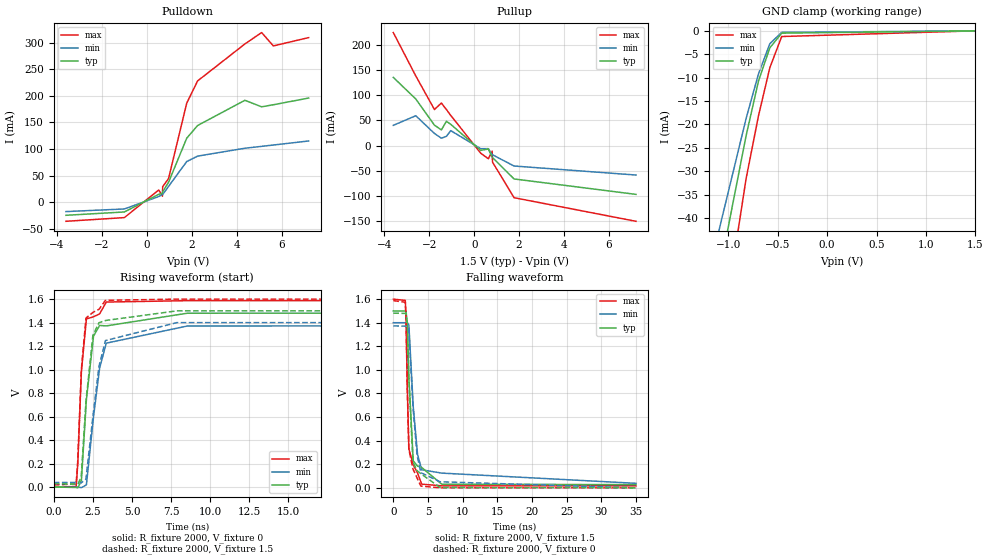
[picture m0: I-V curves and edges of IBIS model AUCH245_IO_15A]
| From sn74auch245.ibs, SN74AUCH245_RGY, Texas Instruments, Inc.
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[Model]   AUCH245_IO_15A
Model_type  3-state
Enable   Active-Low
Vref =   0
Rref =   2000
Cref =   15p
Vmeas =   0.75
| variable   typ   min   max
C_comp   7.04pF   6.32pF   7.63pF
| C_pullup   6.12pF   0.52pF   11.37pF
| C_pulldown   7.96pF   7.02pF   12.32pF
| C_tri-state   7.04pF   6.32pF   7.63pF
[Temperature Range]   40   100   -40
| Ambient temperature   25   85   -40
[Voltage range]   1.5   1.4   1.6
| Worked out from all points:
|   slope of the pulldown table from 0 to 0.225 V, typ, clamps not added: 37.5 ohm
|   slope of the pullup table from 0 to 0.225 V, typ, clamps not added: 29.9 ohm
|   GND clamp passes 1 mA (typ) near -0.50 V on its own axis
|   rising waveform, R_fixture 2000, V_fixture 0: 20-80 % time 506ps typ, 730ps min, 328ps max; typ from 0 V to 1.48 V
|   falling waveform, R_fixture 2000, V_fixture 1.5: 20-80 % time 582ps typ, 905ps min, 360ps max; typ from 1.5 V to 0.027 V
|   rising waveform, R_fixture 2000, V_fixture 1.5: 20-80 % time 501ps typ, 726ps min, 324ps max; typ from 0.027 V to 1.5 V
|   falling waveform, R_fixture 2000, V_fixture 0: 20-80 % time 583ps typ, 908ps min, 359ps max; typ from 1.48 V to 0 V
[GND Clamp]
| AUCH245_IO_15A
|   Voltage   I(typ)   I(min)   I(max)
-3.6V     -348.4mA   -291.7mA   -422.1mA
-1.41V    -88.34mA   -72.2mA    -113.8mA
-1.36V    -82.53mA   -67.43mA   -106.7mA
-1.27V    -72.14mA   -58.93mA   -93.93mA
-1.225V   -66.97mA   -54.72mA   -87.55mA
-1.115V   -54.46mA   -44.56mA   -72.01mA
-1.08V    -50.52mA   -41.37mA   -67.08mA
-820mV    -22.42mA   -18.74mA   -31.59mA
-695mV    -10.75mA   -9.22mA    -18.2mA
-580mV    -3.637mA   -2.754mA   -7.888mA
-460mV    -498.7uA   -331.2uA   -1.219mA
1.5V      904.5pA    545.7nA    20.6pA
[Pulldown]
| AUCH245_IO_15A
|   Voltage   I(typ)   I(min)   I(max)
-3.6V     -24.49mA   -17.53mA   -35.78mA
-1V       -18.24mA   -12.59mA   -28.84mA
530mV     14.93mA    10.83mA    23.06mA
695mV     16.87mA    14.39mA    11.34mA
705mV     19.65mA    14.68mA    29.43mA
965mV     37.43mA    29.69mA    44.37mA
1.775V    120.4mA    76.56mA    186.3mA
2.26V     144.3mA    86.75mA    228.1mA
4.365V    191.7mA    101.6mA    297.6mA
5.11V     179.4mA    105.1mA    319mA
5.63V     183.3mA    107.6mA    293.9mA
7.2V      195.9mA    115.2mA    309.5mA
[Pullup]
| AUCH245_IO_15A
|   Voltage   I(typ)   I(min)   I(max)
-3.6V     135.5mA    40.29mA    224.6mA
-2.6V     92.66mA    59.33mA    138.4mA
-1.77V    40.63mA    24.16mA    71.7mA
-1.46V    31.15mA    14.74mA    84.63mA
-1.235V   48.3mA     18.48mA    71.55mA
-1.045V   42.35mA    29.79mA    60.05mA
290mV     -9.433mA   -6.112mA   -15.03mA
630mV     -6.806mA   -6.067mA   -26.14mA
800mV     -23.19mA   -17.72mA   -11.18mA
815mV     -23.73mA   -18.24mA   -32.73mA
1.775V    -66.25mA   -40.56mA   -103.5mA
7.2V      -96.9mA    -58.48mA   -150.4mA
[Ramp]
| AUCH245_IO_15A
| variable   typ   min   max
dV/dt_r   0.89/5.12E-10   0.83/7.32E-10   0.96/3.34E-10
dV/dt_f   0.88/5.85E-10   0.82/9.06E-10   0.95/3.62E-10
R_load = 2000
[Rising Waveform]
| AUCH245_IO_15A
R_fixture =   2000
C_fixture =   0
L_fixture =   0
V_fixture =   0
V_fixture_min = 0
V_fixture_max = 0
|   Time   V(typ)   V(min)   V(max)
0s        11.12nV    44.9nV     761.8pV
1.43ns    -3.973mV   76.14uV    4.037mV
1.535ns   -7.306mV   -1.152mV   201.5mV
1.765ns   54.68mV    -5.732mV   985.5mV
2.085ns   745.1mV    18.57mV    1.431V
2.54ns    1.285V     598.7mV    1.45V
2.93ns    1.376V     1.012V     1.474V
3.355ns   1.372V     1.225V     1.575V
8.54ns    1.48V      1.371V     1.587V
34.99ns   1.481V     1.373V     1.587V
[Falling Waveform]
| AUCH245_IO_15A
R_fixture =   2000
C_fixture =   0
L_fixture =   0
V_fixture =   1.5
V_fixture_min = 1.4
V_fixture_max = 1.6
|   Time   V(typ)   V(min)   V(max)
0s        1.5V       1.4V       1.6V
1.725ns   1.5V       1.4V       1.589V
1.83ns    1.498V     1.401V     1.461V
2.015ns   1.402V     1.402V     851.4mV
2.245ns   934.7mV    1.38V      331.8mV
2.875ns   228.5mV    686.8mV    194.1mV
3.495ns   184.4mV    283.4mV    126.5mV
4.09ns    173mV      153.2mV    31.56mV
6.99ns    30.84mV    125mV      17.14mV
34.99ns   27.37mV    38.43mV    16.77mV
[Rising Waveform]
| AUCH245_IO_15A
R_fixture =   2000
C_fixture =   0
L_fixture =   0
V_fixture =   1.5
V_fixture_min = 1.4
V_fixture_max = 1.6
|   Time   V(typ)   V(min)   V(max)
0s        27.32mV    38.39mV    16.75mV
1.43ns    24.39mV    38.6mV     26.06mV
1.535ns   22.34mV    37.7mV     232.2mV
1.755ns   86.93mV    35.37mV    990.2mV
2.055ns   726.4mV    66.17mV    1.438V
2.5ns     1.292V     598.6mV    1.487V
2.89ns    1.399V     1.029V     1.513V
3.305ns   1.418V     1.247V     1.59V
7.87ns    1.5V       1.4V       1.6V
34.99ns   1.5V       1.4V       1.6V
[Falling Waveform]
| AUCH245_IO_15A
R_fixture =   2000
C_fixture =   0
L_fixture =   0
V_fixture =   0
V_fixture_min = 0
V_fixture_max = 0
|   Time   V(typ)   V(min)   V(max)
0s        1.481V     1.373V     1.587V
1.725ns   1.479V     1.371V     1.574V
1.83ns    1.476V     1.371V     1.447V
2.01ns    1.379V     1.371V     853.7mV
2.235ns   933.4mV    1.346V     328.5mV
2.835ns   219.9mV    687.6mV    160.1mV
3.43ns    145.1mV    274.2mV    83.57mV
3.98ns    119.6mV    128.5mV    14.56mV
6.75ns    2.99mV     51.58mV    407.2uV
34.99ns   49.25uV    36.46uV    19.8uV
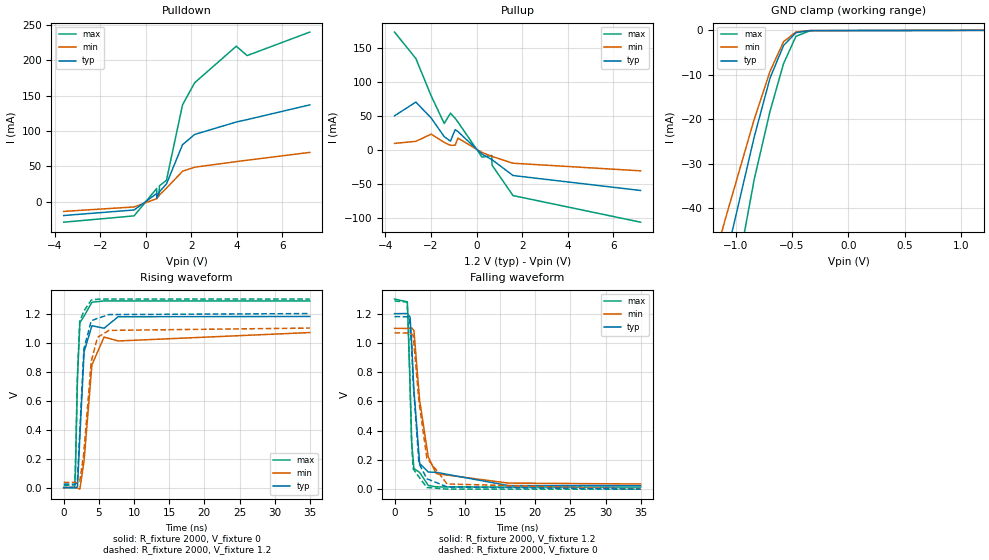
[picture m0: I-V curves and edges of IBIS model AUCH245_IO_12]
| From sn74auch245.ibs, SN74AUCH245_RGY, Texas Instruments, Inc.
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[Model]   AUCH245_IO_12
Model_type  3-state
Enable   Active-Low
Vref =   0
Rref =   2000
Cref =   15p
Vmeas =   0.6
| variable   typ   min   max
C_comp   7.13pF   6.44pF   7.70pF
| C_pullup   6.10pF   0.47pF   9.81pF
| C_pulldown   7.79pF   7.02pF   8.67pF
| C_tri-state   7.13pF   6.44pF   7.70pF
[Temperature Range]   40   100   -40
| Ambient temperature   25   85   -40
[Voltage range]   1.2   1.1   1.3
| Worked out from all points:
|   slope of the pulldown table from 0 to 0.18 V, typ, clamps not added: 42.4 ohm
|   slope of the pullup table from 0 to 0.18 V, typ, clamps not added: 39.1 ohm
|   GND clamp passes 1 mA (typ) near -0.50 V on its own axis
|   rising waveform, R_fixture 2000, V_fixture 0: 20-80 % time 703ps typ, 1.1ns min, 420ps max; typ from 0 V to 1.18 V
|   falling waveform, R_fixture 2000, V_fixture 1.2: 20-80 % time 887ps typ, 1.51ns min, 464ps max; typ from 1.2 V to 0.024 V
|   rising waveform, R_fixture 2000, V_fixture 1.2: 20-80 % time 691ps typ, 1.09ns min, 414ps max; typ from 0.024 V to 1.2 V
|   falling waveform, R_fixture 2000, V_fixture 0: 20-80 % time 880ps typ, 1.48ns min, 460ps max; typ from 1.18 V to 0 V
[GND Clamp]
| AUCH245_IO_12
|   Voltage   I(typ)   I(min)   I(max)
-3.6V     -348.4mA   -291.7mA   -422.1mA
-1.395V   -86.59mA   -70.76mA   -111.6mA
-1.345V   -80.79mA   -66.01mA   -104.5mA
-1.255V   -70.41mA   -57.52mA   -91.78mA
-1.21V    -65.25mA   -53.32mA   -85.41mA
-1.09V    -51.64mA   -42.28mA   -68.47mA
-835mV    -23.94mA   -19.97mA   -33.46mA
-695mV    -10.73mA   -9.215mA   -18.19mA
-575mV    -3.409mA   -2.552mA   -7.477mA
-465mV    -538.4uA   -354.6uA   -1.338mA
-340mV    -56.85uA   -46.84uA   -97.22uA
1.2V      742pA      544.5nA    -10.19pA
[Pulldown]
| AUCH245_IO_12
|   Voltage   I(typ)   I(min)   I(max)
-3.6V     -19.68mA   -13.85mA   -29.13mA
-510mV    -11.83mA   -7.547mA   -20.17mA
480mV     11.48mA    4.194mA    18.61mA
485mV     5.028mA    4.242mA    6.734mA
590mV     13.72mA    9.189mA    8.369mA
600mV     13.91mA    9.311mA    22.36mA
910mV     25.04mA    19.15mA    30.29mA
1.615V    80.69mA    43.04mA    137.1mA
2.15V     95.19mA    48.79mA    168.5mA
3.975V    112.8mA    56.68mA    220.2mA
4.45V     116.2mA    58.66mA    206.9mA
7.2V      137.1mA    69.78mA    240.2mA
[Pullup]
| AUCH245_IO_12
|   Voltage   I(typ)   I(min)   I(max)
-3.6V     50.58mA    10.01mA    173.6mA
-2.665V   70.72mA    13.03mA    134.8mA
-1.99V    47.23mA    23.6mA     79.7mA
-1.42V    19.97mA    11.47mA    39.36mA
-1.145V   13.31mA    7.138mA    54.39mA
-940mV    30.29mA    7.312mA    46.87mA
-815mV    27.3mA     17.76mA    41.21mA
240mV     -5.822mA   -3.33mA    -10.26mA
665mV     -13.73mA   -9.09mA    -7.68mA
680mV     -13.93mA   -9.242mA   -22.01mA
1.6V      -37.2mA    -19.13mA   -66.69mA
7.2V      -59.19mA   -30.31mA   -105.8mA
[Ramp]
| AUCH245_IO_12
| variable   typ   min   max
dV/dt_r   0.71/7.07E-10   0.65/1.11E-09   0.78/4.22E-10
dV/dt_f   0.71/8.91E-10   0.64/1.51E-09   0.77/4.65E-10
R_load = 2000
[Rising Waveform]
| AUCH245_IO_12
R_fixture =   2000
C_fixture =   0
L_fixture =   0
V_fixture =   0
V_fixture_min = 0
V_fixture_max = 0
|   Time   V(typ)   V(min)   V(max)
0s        10.41nV    46.55nV    639.7pV
1.55ns    -1.906mV   937.6uV    3.31mV
1.665ns   -3.894mV   230.5uV    107.7mV
1.965ns   7.148mV    -3.201mV   766.6mV
2.3ns     354.8mV    -10.78mV   1.136V
2.9ns     936.7mV    188.5mV    1.183V
4.01ns    1.116V     846.5mV    1.278V
5.74ns    1.099V     1.038V     1.287V
7.74ns    1.178V     1.011V     1.287V
34.99ns   1.18V      1.069V     1.287V
[Falling Waveform]
| AUCH245_IO_12
R_fixture =   2000
C_fixture =   0
L_fixture =   0
V_fixture =   1.2
V_fixture_min = 1.1
V_fixture_max = 1.3
|   Time   V(typ)   V(min)   V(max)
0s        1.2V       1.1V       1.3V
1.82ns    1.201V     1.099V     1.281V
2.21ns    1.176V     1.101V     716.1mV
2.445ns   986.6mV    1.102V     312.7mV
2.755ns   675.7mV    1.085V     140.8mV
3.57ns    175.9mV    607.6mV    114.7mV
4.79ns    117.2mV    221.8mV    25.98mV
5.925ns   115.3mV    106.2mV    15.71mV
16.2ns    24.28mV    41.45mV    14.4mV
34.99ns   24.14mV    35.41mV    14.35mV
[Rising Waveform]
| AUCH245_IO_12
R_fixture =   2000
C_fixture =   0
L_fixture =   0
V_fixture =   1.2
V_fixture_min = 1.1
V_fixture_max = 1.3
|   Time   V(typ)   V(min)   V(max)
0s        24.08mV    35.36mV    14.32mV
1.54ns    22.94mV    36.16mV    19.5mV
1.66ns    21.99mV    35.64mV    127.4mV
1.94ns    40.88mV    34.47mV    750.3mV
2.275ns   373.2mV    40.96mV    1.146V
2.865ns   955.8mV    241.4mV    1.217V
3.915ns   1.15V      870.7mV    1.293V
4.805ns   1.167V     1.036V     1.299V
6.44ns    1.193V     1.084V     1.3V
34.99ns   1.2V       1.1V       1.3V
[Falling Waveform]
| AUCH245_IO_12
R_fixture =   2000
C_fixture =   0
L_fixture =   0
V_fixture =   0
V_fixture_min = 0
V_fixture_max = 0
|   Time   V(typ)   V(min)   V(max)
0s        1.18V      1.069V     1.287V
1.765ns   1.179V     1.068V     1.28V
1.92ns    1.179V     1.068V     1.186V
2.155ns   1.162V     1.067V     802.7mV
2.415ns   985.1mV    1.063V     328.7mV
2.65ns    730.8mV    1.052V     138.9mV
3.475ns   175.8mV    598.1mV    82.99mV
4.595ns   71.52mV    213.2mV    11.62mV
7.485ns   15.13mV    35.58mV    342.9uV
34.99ns   52.7uV     35.22uV    29.29uV
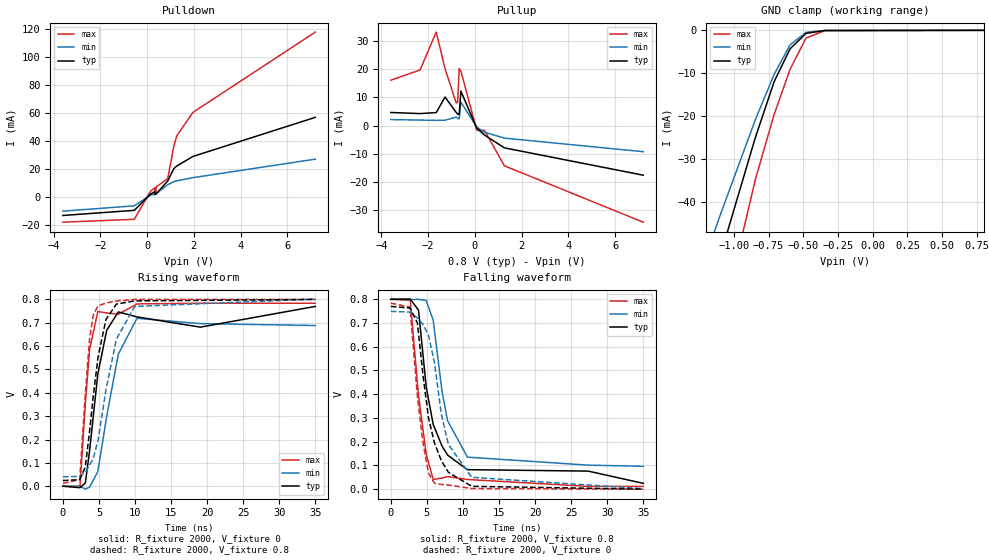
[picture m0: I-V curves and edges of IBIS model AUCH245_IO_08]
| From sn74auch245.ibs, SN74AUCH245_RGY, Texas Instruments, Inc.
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[Model]   AUCH245_IO_08
Model_type  3-state
Enable   Active-Low
Vref =   0
Rref =   2000
Cref =   15p
Vmeas =   0.4
| variable   typ   min   max
C_comp   7.24pF   6.69pF   7.71pF
| C_pullup   7.24pF   2.74pF   10.10pF
| C_pulldown   7.90pF   6.92pF   8.33pF
| C_tri-state   7.24pF   6.69pF   7.71pF
[Temperature Range]   40   100   -40
| Ambient temperature   25   85   -40
[Voltage range]   0.8   0.8   0.8
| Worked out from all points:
|   slope of the pulldown table from 0 to 0.12 V, typ, clamps not added: 71.3 ohm
|   slope of the pullup table from 0 to 0.12 V, typ, clamps not added: 92.5 ohm
|   GND clamp passes 1 mA (typ) near -0.50 V on its own axis
|   rising waveform, R_fixture 2000, V_fixture 0: 20-80 % time 1.9ns typ, 2.28ns min, 1.12ns max; typ from 0 V to 0.77 V
|   falling waveform, R_fixture 2000, V_fixture 0.8: 20-80 % time 2.9ns typ, 2.24ns min, 1.68ns max; typ from 0.8 V to 0.025 V
|   rising waveform, R_fixture 2000, V_fixture 0.8: 20-80 % time 1.87ns typ, 2.75ns min, 1.07ns max; typ from 0.024 V to 0.8 V
|   falling waveform, R_fixture 2000, V_fixture 0: 20-80 % time 2.45ns typ, 2.76ns min, 1.58ns max; typ from 0.77 V to 0 V
[GND Clamp]
| AUCH245_IO_08
|   Voltage   I(typ)   I(min)   I(max)
-3.6V     -348.4mA   -291.7mA   -422mA
-1.435V   -91.23mA   -74.58mA   -117.3mA
-1.385V   -85.42mA   -69.81mA   -110.2mA
-1.285V   -73.85mA   -60.34mA   -96.01mA
-1.24V    -68.68mA   -56.12mA   -89.63mA
-1.105V   -53.32mA   -43.64mA   -70.54mA
-845mV    -24.95mA   -20.79mA   -34.7mA
-710mV    -11.96mA   -10.26mA   -19.61mA
-595mV    -4.291mA   -3.37mA    -9.051mA
-480mV    -710.9uA   -464.9uA   -1.793mA
-345mV    -43.84uA   -41.21uA   -69.34uA
800mV     553.1pA    2.078nA    70.04pA
[Pulldown]
| AUCH245_IO_08
|   Voltage   I(typ)   I(min)   I(max)
-3.6V     -13.19mA   -10.12mA   -17.98mA
-545mV    -9.542mA   -6.309mA   -15.92mA
150mV     2.015mA    1.387mA    4.124mA
335mV     3.795mA    1.858mA    6.516mA
340mV     1.803mA    1.892mA    2.194mA
385mV     2.144mA    2.205mA    2.492mA
390mV     2.182mA    2.24mA     7.071mA
885mV     11.39mA    8.76mA     13.08mA
1.15V     20.27mA    10.96mA    36.31mA
1.275V    22.07mA    11.52mA    43.61mA
1.965V    28.88mA    13.76mA    60.28mA
7.2V      56.73mA    26.94mA    117.5mA
[Pullup]
| AUCH245_IO_08
|   Voltage   I(typ)   I(min)   I(max)
-3.6V     4.661mA    2.141mA    16.15mA
-2.35V    4.263mA    1.959mA    19.76mA
-1.655V   4.621mA    1.842mA    33.26mA
-1.28V    10.16mA    1.92mA     20.22mA
-800mV    4.647mA    3.021mA    8.033mA
-740mV    4.114mA    2.663mA    8.403mA
-675mV    3.902mA    2.342mA    20.25mA
-600mV    12.24mA    8.343mA    19.4mA
75mV      -881.5uA   -518.8uA   -1.613mA
410mV     -3.383mA   -2.391mA   -1.706mA
1.26V     -7.924mA   -4.451mA   -14.31mA
7.2V      -17.65mA   -9.293mA   -34.37mA
[Ramp]
| AUCH245_IO_08
| variable   typ   min   max
dV/dt_r   0.47/1.92E-09   0.45/2.63E-09   0.48/1.13E-09
dV/dt_f   0.47/2.90E-09   0.42/2.26E-09   0.47/1.69E-09
R_load = 2000
[Rising Waveform]
| AUCH245_IO_08
R_fixture =   2000
C_fixture =   0
L_fixture =   0
V_fixture =   0
V_fixture_min = 0
V_fixture_max = 0
|   Time   V(typ)   V(min)   V(max)
0s        12.24nV    63.6nV     536.5pV
2.37ns    -6.265mV   -984.9uV   209.6uV
3.115ns   14.23mV    -12.64mV   355.2mV
3.7ns     151.7mV    -4.264mV   585.4mV
4.84ns    480.7mV    62.89mV    748mV
6.075ns   668.1mV    299.8mV    742.1mV
7.68ns    746.4mV    565.3mV    736.5mV
10.27ns   725.1mV    719.1mV    780.7mV
19.06ns   681.2mV    696.4mV    783.7mV
34.99ns   770mV      688.2mV    783.7mV
[Falling Waveform]
| AUCH245_IO_08
R_fixture =   2000
C_fixture =   0
L_fixture =   0
V_fixture =   0.8
V_fixture_min = 0.8
V_fixture_max = 0.8
|   Time   V(typ)   V(min)   V(max)
0s        800mV      800mV      800mV
2.695ns   800.9mV    799.1mV    795.7mV
3.84ns    754mV      799.7mV    393.7mV
4.915ns   428.4mV    794.9mV    146.7mV
5.875ns   273mV      711.2mV    40.99mV
7.09ns    182.1mV    414.1mV    46.89mV
7.865ns   143.8mV    288.6mV    53.07mV
10.62ns   82.18mV    134.9mV    40.81mV
27.35ns   76.12mV    101.3mV    11.84mV
34.99ns   24.64mV    96.4mV     11.82mV
[Rising Waveform]
| AUCH245_IO_08
R_fixture =   2000
C_fixture =   0
L_fixture =   0
V_fixture =   0.8
V_fixture_min = 0.8
V_fixture_max = 0.8
|   Time   V(typ)   V(min)   V(max)
0s        24.28mV    40.78mV    11.78mV
2.33ns    28.11mV    41.61mV    28.69mV
3.1ns     81.78mV    59.39mV    393.1mV
3.695ns   234.1mV    89.42mV    630.6mV
4.21ns    386.3mV    120.3mV    733mV
4.865ns   551.3mV    195.1mV    771.9mV
5.965ns   713.6mV    412.5mV    784.8mV
7.41ns    780mV      629.5mV    793mV
9.95ns    793.6mV    770mV      799.9mV
34.99ns   799.9mV    801.5mV    800mV
[Falling Waveform]
| AUCH245_IO_08
R_fixture =   2000
C_fixture =   0
L_fixture =   0
V_fixture =   0
V_fixture_min = 0
V_fixture_max = 0
|   Time   V(typ)   V(min)   V(max)
0s        770mV      748.8mV    783.8mV
2.655ns   763.1mV    746.2mV    767.1mV
3.685ns   700.4mV    721.7mV    391.9mV
4.445ns   483.7mV    694.9mV    198.5mV
5.225ns   300.4mV    648.3mV    67.51mV
6.06ns    193.7mV    531.1mV    24.49mV
7ns       120.7mV    316.1mV    19.71mV
7.98ns    71.11mV    188.5mV    17.4mV
11.22ns   11.96mV    49.97mV    2.733mV
34.99ns   122uV      2.248mV    33.61uV
